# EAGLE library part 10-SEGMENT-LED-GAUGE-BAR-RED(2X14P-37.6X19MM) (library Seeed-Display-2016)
304080004

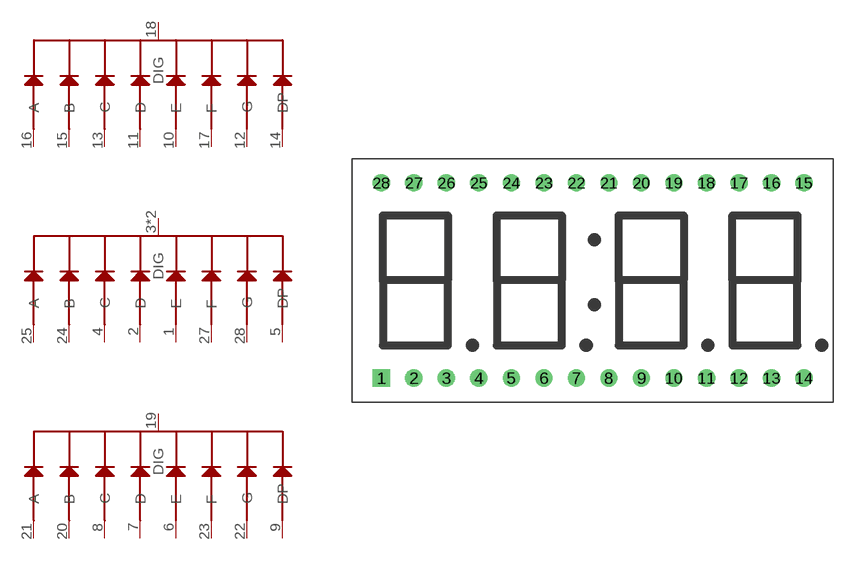
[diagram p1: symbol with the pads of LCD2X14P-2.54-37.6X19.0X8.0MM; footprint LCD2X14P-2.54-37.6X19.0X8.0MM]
Designator prefix LCD; gates G$1=LED-DISPLAY-7P G$2=LED-DISPLAY-7P G$3=LED-DISPLAY-7P

## 10-SEGMENT-LED-GAUGE-BAR-RED(2X14P-37.6X19MM) (MPN: SP400561N; VALUE: SP400561N)  [LCD2X14P-2.54-37.6X19.0X8.0MM]
1  G$1:E
2  G$1:D
3  G$1:DIG
4  G$1:C
5  G$1:DP
6  G$2:E
7  G$2:D
8  G$2:C
9  G$2:DP
10  G$3:E
11  G$3:D
12  G$3:G
13  G$3:C
14  G$3:DP
15  G$3:B
16  G$3:A
17  G$3:F
18  G$3:DIG
19  G$2:DIG
20  G$2:B
21  G$2:A
22  G$2:G
23  G$2:F
24  G$1:B
25  G$1:A
26  G$1:DIG
27  G$1:F
28  G$1:G

## Footprint LCD2X14P-2.54-37.6X19.0X8.0MM (pad centres in mm)
drill 0.8 pad 1.35 square: 1 -16.51,-7.62
drill 0.8 pad 1.35: 2 -13.97,-7.62; 3 -11.43,-7.62; 4 -8.89,-7.62; 5 -6.35,-7.62; 6 -3.81,-7.62; 7 -1.27,-7.62; 8 1.27,-7.62; 9 3.81,-7.62; 10 6.35,-7.62; 11 8.89,-7.62; 12 11.43,-7.62; 13 13.97,-7.62; 14 16.51,-7.62; 15 16.51,7.62; 16 13.97,7.62; 17 11.43,7.62; 18 8.89,7.62; 19 6.35,7.62; 20 3.81,7.62; 21 1.27,7.62; 22 -1.27,7.62; 23 -3.81,7.62; 24 -6.35,7.62; 25 -8.89,7.62; 26 -11.43,7.62; 27 -13.97,7.62; 28 -16.51,7.62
